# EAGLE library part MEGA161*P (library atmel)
MICROCONTROLLER 16 Kbytes FLASH 512 bytes EEPROM 1 Kbytes SRAM dual UART hardware multiplier Source: avr.lbr

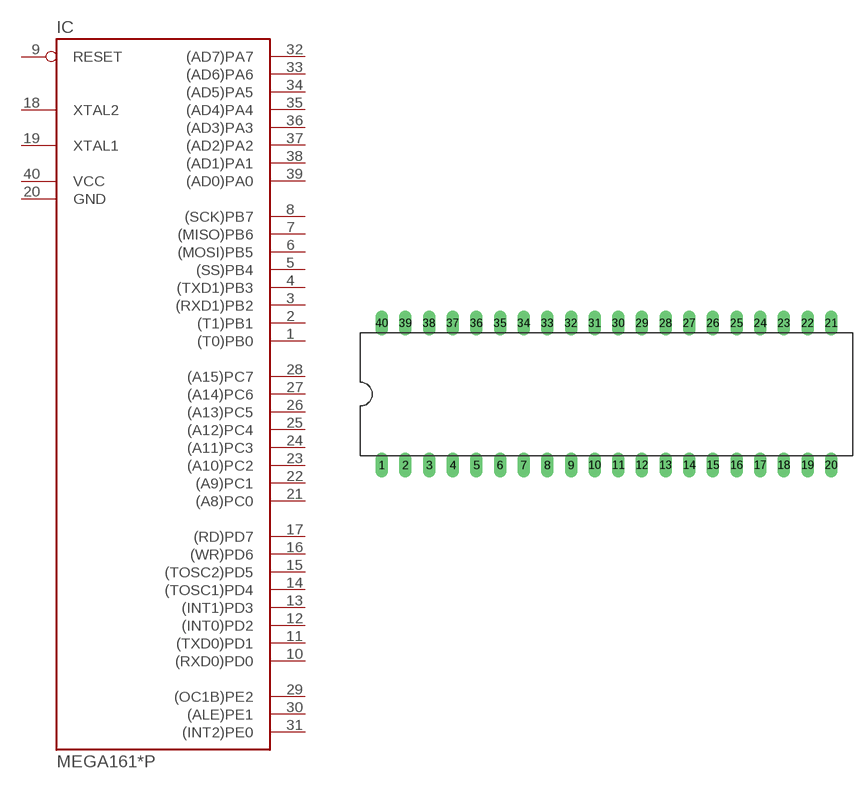
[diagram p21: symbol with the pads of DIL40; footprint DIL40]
Designator prefix IC

## MEGA161P (MPN: ATMEGA16-16PU; OC_FARNELL: 9171142; OC_NEWARK: 98M0167), MEGA161LP (MPN: ATMEGA16-16PU; OC_FARNELL: 9171142; OC_NEWARK: 98M0167)  [DIL40]
1  (T0)PB0
2  (T1)PB1
3  (RXD1)PB2
4  (TXD1)PB3
5  (SS)PB4
6  (MOSI)PB5
7  (MISO)PB6
8  (SCK)PB7
9  RESET  in
10  (RXD0)PD0
11  (TXD0)PD1
12  (INT0)PD2
13  (INT1)PD3
14  (TOSC1)PD4
15  (TOSC2)PD5
16  (WR)PD6
17  (RD)PD7
18  XTAL2  in
19  XTAL1  in
20  GND  pwr
21  (A8)PC0
22  (A9)PC1
23  (A10)PC2
24  (A11)PC3
25  (A12)PC4
26  (A13)PC5
27  (A14)PC6
28  (A15)PC7
29  (OC1B)PE2
30  (ALE)PE1
31  (INT2)PE0
32  (AD7)PA7
33  (AD6)PA6
34  (AD5)PA5
35  (AD4)PA4
36  (AD3)PA3
37  (AD2)PA2
38  (AD1)PA1
39  (AD0)PA0
40  VCC  pwr

## Footprint DIL40 (pad centres in mm)
Dual In Line
drill 0.813 long: 1 -24.13,-7.62; 2 -21.59,-7.62; 3 -19.05,-7.62; 4 -16.51,-7.62; 5 -13.97,-7.62; 6 -11.43,-7.62; 7 -8.89,-7.62; 8 -6.35,-7.62; 9 -3.81,-7.62; 10 -1.27,-7.62; 11 1.27,-7.62; 12 3.81,-7.62; 13 6.35,-7.62; 14 8.89,-7.62; 15 11.43,-7.62; 16 13.97,-7.62; 17 16.51,-7.62; 18 19.05,-7.62; 19 21.59,-7.62; 20 24.13,-7.62; 21 24.13,7.62; 22 21.59,7.62; 23 19.05,7.62; 24 16.51,7.62; 25 13.97,7.62; 26 11.43,7.62; 27 8.89,7.62; 28 6.35,7.62; 29 3.81,7.62; 30 1.27,7.62; 31 -1.27,7.62; 32 -3.81,7.62; 33 -6.35,7.62; 34 -8.89,7.62; 35 -11.43,7.62; 36 -13.97,7.62; 37 -16.51,7.62; 38 -19.05,7.62; 39 -21.59,7.62; 40 -24.13,7.62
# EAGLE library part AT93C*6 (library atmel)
3-wire serial EEPROM

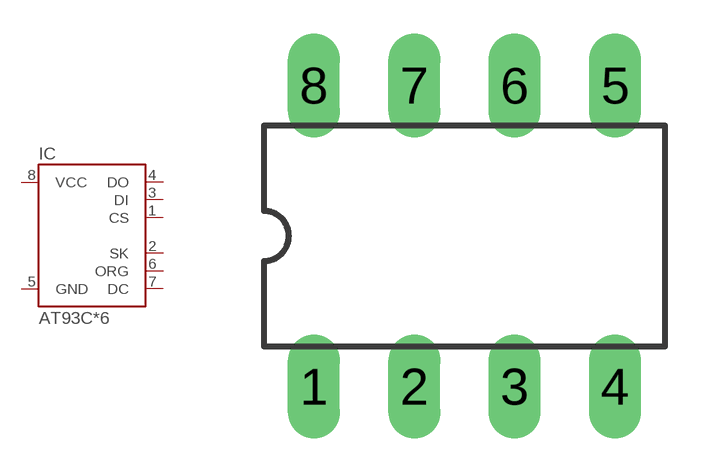
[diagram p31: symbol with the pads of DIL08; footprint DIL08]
Designator prefix IC

## AT93C6P (MPN: AT93C46D-PU; OC_FARNELL: 1362666; OC_NEWARK: 50M3339)  [DIL08]
1  CS  in
2  SK
3  DI  in
4  DO  out
5  GND  pwr
6  ORG  in
7  DC  in
8  VCC  pwr

## Footprint DIL08 (pad centres in mm)
Dual In Line
drill 0.813 long: 1 -3.81,-3.81; 2 -1.27,-3.81; 3 1.27,-3.81; 4 3.81,-3.81; 5 3.81,3.81; 6 1.27,3.81; 7 -1.27,3.81; 8 -3.81,3.81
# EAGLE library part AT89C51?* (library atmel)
8-bit Microcontroller with 4K Bytes Flash Not Recommended for New Designs. Use AT89S51. Source: http://www.atmel.com/dyn/resources/prod_documents/doc0265.

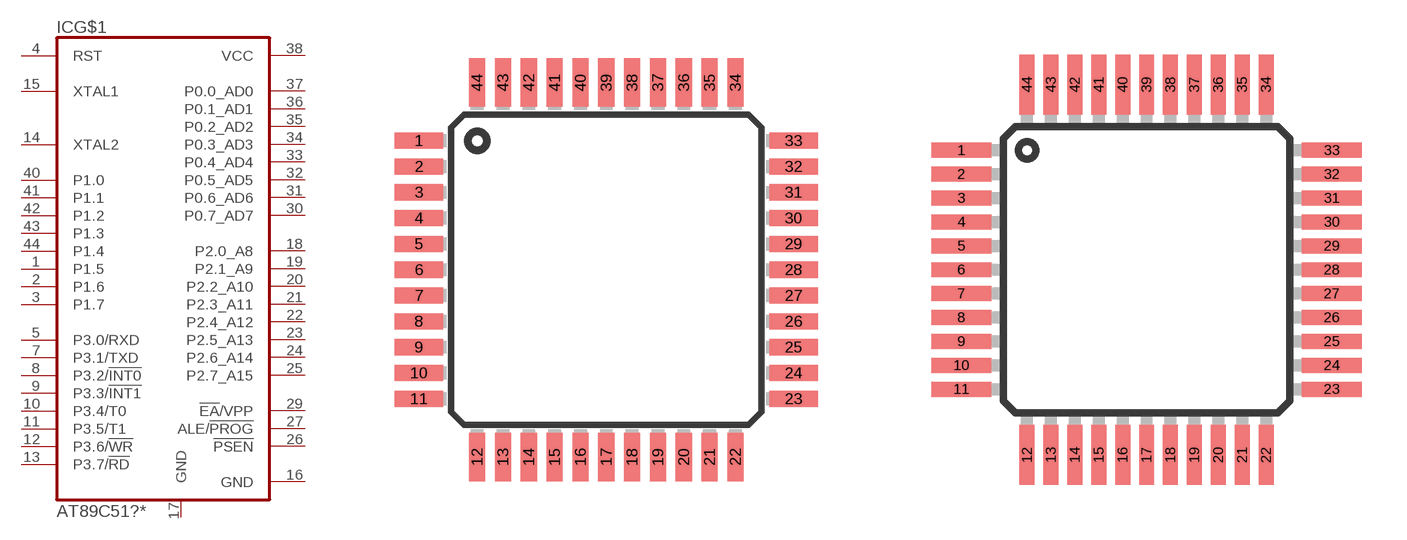
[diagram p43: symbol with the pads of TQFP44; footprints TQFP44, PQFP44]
Designator prefix IC; gates G$1=AT89C51 P=GND

## AT89C51AC-12 (OC_FARNELL: unknown; OC_NEWARK: unknown), AT89C51AC-16 (OC_FARNELL: unknown; OC_NEWARK: unknown), AT89C51AC-20 (OC_FARNELL: unknown; OC_NEWARK: unknown), AT89C51AC-24 (OC_FARNELL: unknown; OC_NEWARK: unknown)  [TQFP44]
1  G$1:P1.5
2  G$1:P1.6
3  G$1:P1.7
4  G$1:RST  in
5  G$1:P3.0/RXD
7  G$1:P3.1/TXD
8  G$1:P3.2/!INT0
9  G$1:P3.3/!INT1
10  G$1:P3.4/T0
11  G$1:P3.5/T1
12  G$1:P3.6/!WR
13  G$1:P3.7/!RD
14  G$1:XTAL2  in
15  G$1:XTAL1  in
16  G$1:GND  pwr
17  P:GND  pwr
18  G$1:P2.0_A8
19  G$1:P2.1_A9
20  G$1:P2.2_A10
21  G$1:P2.3_A11
22  G$1:P2.4_A12
23  G$1:P2.5_A13
24  G$1:P2.6_A14
25  G$1:P2.7_A15
26  G$1:!PSEN  out
27  G$1:ALE/!PROG  out
29  G$1:!EA!/VPP  in
30  G$1:P0.7_AD7
31  G$1:P0.6_AD6
32  G$1:P0.5_AD5
33  G$1:P0.4_AD4
34  G$1:P0.3_AD3
35  G$1:P0.2_AD2
36  G$1:P0.1_AD1
37  G$1:P0.0_AD0
38  G$1:VCC  pwr
40  G$1:P1.0
41  G$1:P1.1
42  G$1:P1.2
43  G$1:P1.3
44  G$1:P1.4

## AT89C51QC-12 (OC_FARNELL: unknown; OC_NEWARK: unknown), AT89C51QC-16 (OC_FARNELL: unknown; OC_NEWARK: unknown), AT89C51QC-20 (OC_FARNELL: unknown; OC_NEWARK: unknown), AT89C51QC-24 (OC_FARNELL: unknown; OC_NEWARK: unknown)  [PQFP44]
Pads as for TQFP44

## Footprint TQFP44 (pad centres in mm)
44-lead Thin Quad Flat Package
smd 1.5 x 0.5: 1 -5.8,4; 2 -5.8,3.2; 3 -5.8,2.4; 4 -5.8,1.6; 5 -5.8,0.8; 6 -5.8,0; 7 -5.8,-0.8; 8 -5.8,-1.6; 9 -5.8,-2.4; 10 -5.8,-3.2; 11 -5.8,-4; 23 5.8,-4; 24 5.8,-3.2; 25 5.8,-2.4; 26 5.8,-1.6; 27 5.8,-0.8; 28 5.8,0; 29 5.8,0.8; 30 5.8,1.6; 31 5.8,2.4; 32 5.8,3.2; 33 5.8,4
smd 0.5 x 1.5: 12 -4,-5.8; 13 -3.2,-5.8; 14 -2.4,-5.8; 15 -1.6,-5.8; 16 -0.8,-5.8; 17 0,-5.8; 18 0.8,-5.8; 19 1.6,-5.8; 20 2.4,-5.8; 21 3.2,-5.8; 22 4,-5.8; 34 4,5.8; 35 3.2,5.8; 36 2.4,5.8; 37 1.6,5.8; 38 0.8,5.8; 39 0,5.8; 40 -0.8,5.8; 41 -1.6,5.8; 42 -2.4,5.8; 43 -3.2,5.8; 44 -4,5.8

## Footprint PQFP44 (pad centres in mm)
Plastic Quad Flat Package
smd 2 x 0.5: 1 -6.2,4; 2 -6.2,3.2; 3 -6.2,2.4; 4 -6.2,1.6; 5 -6.2,0.8; 6 -6.2,0; 7 -6.2,-0.8; 8 -6.2,-1.6; 9 -6.2,-2.4; 10 -6.2,-3.2; 11 -6.2,-4; 23 6.2,-4; 24 6.2,-3.2; 25 6.2,-2.4; 26 6.2,-1.6; 27 6.2,-0.8; 28 6.2,0; 29 6.2,0.8; 30 6.2,1.6; 31 6.2,2.4; 32 6.2,3.2; 33 6.2,4
smd 0.5 x 2: 12 -4,-6.2; 13 -3.2,-6.2; 14 -2.4,-6.2; 15 -1.6,-6.2; 16 -0.8,-6.2; 17 0,-6.2; 18 0.8,-6.2; 19 1.6,-6.2; 20 2.4,-6.2; 21 3.2,-6.2; 22 4,-6.2; 34 4,6.2; 35 3.2,6.2; 36 2.4,6.2; 37 1.6,6.2; 38 0.8,6.2; 39 0,6.2; 40 -0.8,6.2; 41 -1.6,6.2; 42 -2.4,6.2; 43 -3.2,6.2; 44 -4,6.2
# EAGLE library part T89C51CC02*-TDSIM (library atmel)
Enhanced 8-bit Microcontroller with CAN Controller and Flash 80C51 Core Architecture Source: http://www.atmel.com/dyn/resources/prod_documents/doc4126.

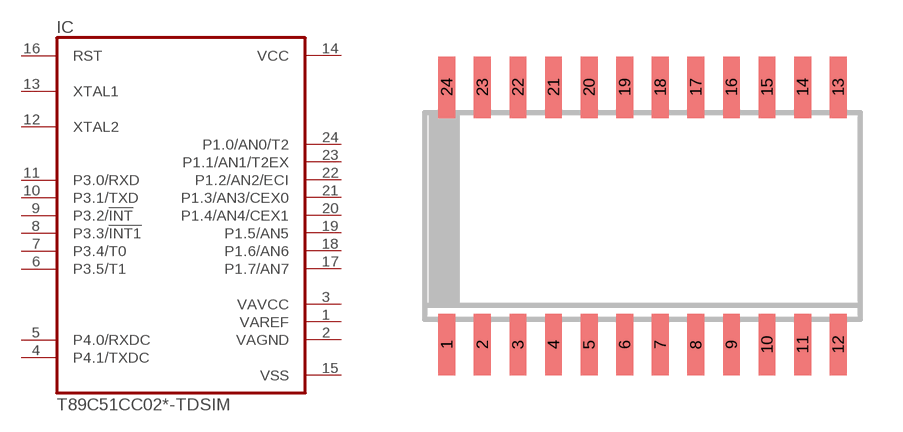
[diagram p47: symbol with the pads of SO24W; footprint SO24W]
Designator prefix IC

## T89C51CC02CA-TDSIM (OC_FARNELL: unknown; OC_NEWARK: unknown), T89C51CC02UA-TDSIM (OC_FARNELL: unknown; OC_NEWARK: unknown)  [SO24W]
1  VAREF  in
2  VAGND  in
3  VAVCC  in
4  P4.1/TXDC
5  P4.0/RXDC
6  P3.5/T1
7  P3.4/T0
8  P3.3/!INT1
9  P3.2/!INT
10  P3.1/TXD
11  P3.0/RXD
12  XTAL2  in
13  XTAL1  in
14  VCC  pwr
15  VSS  pwr
16  RST  in
17  P1.7/AN7
18  P1.6/AN6
19  P1.5/AN5
20  P1.4/AN4/CEX1
21  P1.3/AN3/CEX0
22  P1.2/AN2/ECI
23  P1.1/AN1/T2EX
24  P1.0/AN0/T2

## Footprint SO24W (pad centres in mm)
SMALL OUTLINE INTEGRATED CIRCUIT wide body 7.5 mm/JEDEC MO-119AA Source: http://www.atmel.com/dyn/resources/prod_documents/doc4126.pdf
smd 0.6 x 2.2: 1 -6.985,-4.6; 2 -5.715,-4.6; 3 -4.445,-4.6; 4 -3.175,-4.6; 5 -1.905,-4.6; 6 -0.635,-4.6; 7 0.635,-4.6; 8 1.905,-4.6; 9 3.175,-4.6; 10 4.445,-4.6; 11 5.715,-4.6; 12 6.985,-4.6; 13 6.985,4.6; 14 5.715,4.6; 15 4.445,4.6; 16 3.175,4.6; 17 1.905,4.6; 18 0.635,4.6; 19 -0.635,4.6; 20 -1.905,4.6; 21 -3.175,4.6; 22 -4.445,4.6; 23 -5.715,4.6; 24 -6.985,4.6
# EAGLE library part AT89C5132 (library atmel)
USB Microcontroller with 64K Bytes Flash Memory Source: http://www.atmel.com/dyn/resources/prod_documents/doc4173.pdf

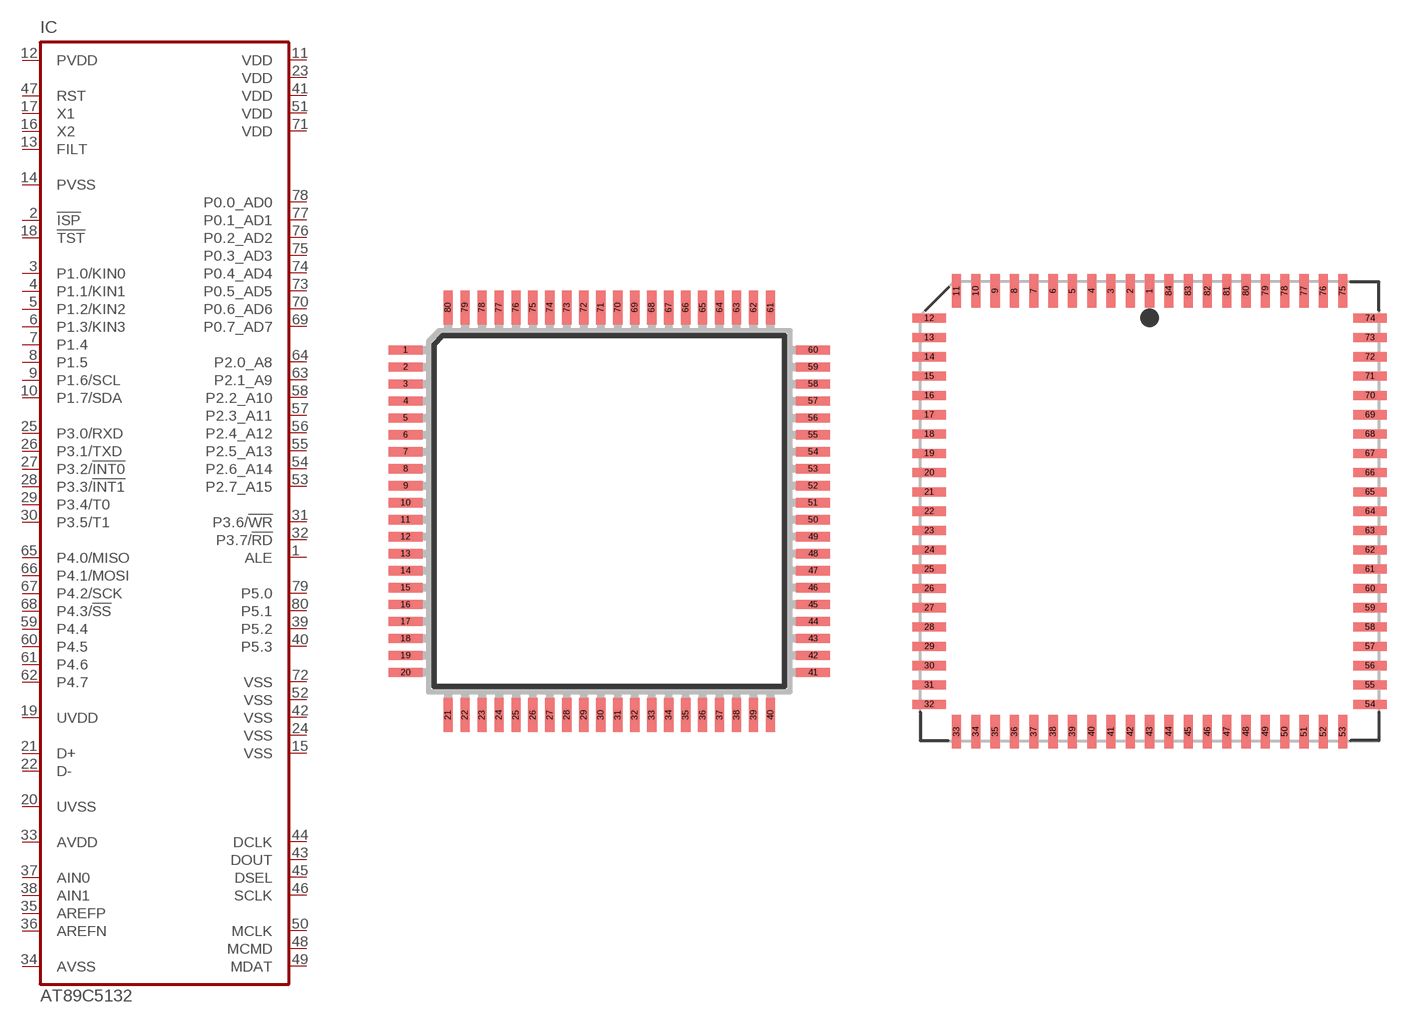
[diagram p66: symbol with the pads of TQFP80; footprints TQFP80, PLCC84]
Designator prefix IC

## AT89C5132 (OC_FARNELL: unknown; OC_NEWARK: unknown)  [TQFP80]
1  ALE
2  !ISP
3  P1.0/KIN0
4  P1.1/KIN1
5  P1.2/KIN2
6  P1.3/KIN3
7  P1.4
8  P1.5
9  P1.6/SCL
10  P1.7/SDA
11  VDD  pwr
12  PVDD  pwr
13  FILT  in
14  PVSS  pwr
15  VSS  pwr
16  X2  in
17  X1  in
18  !TST  in
19  UVDD  pwr
20  UVSS  pwr
21  D+
22  D-
23  VDD  pwr
24  VSS  pwr
25  P3.0/RXD
26  P3.1/TXD
27  P3.2/!INT0
28  P3.3/!INT1
29  P3.4/T0
30  P3.5/T1
31  P3.6/!WR
32  P3.7/!RD
33  AVDD  pwr
34  AVSS  pwr
35  AREFP  in
36  AREFN  in
37  AIN0  in
38  AIN1  in
39  P5.2
40  P5.3
41  VDD  pwr
42  VSS  pwr
43  DOUT  out
44  DCLK  out
45  DSEL  out
46  SCLK  out
47  RST  in
48  MCMD
49  MDAT
50  MCLK  out
51  VDD  pwr
52  VSS  pwr
53  P2.7_A15
54  P2.6_A14
55  P2.5_A13
56  P2.4_A12
57  P2.3_A11
58  P2.2_A10
59  P4.4
60  P4.5
61  P4.6
62  P4.7
63  P2.1_A9
64  P2.0_A8
65  P4.0/MISO
66  P4.1/MOSI
67  P4.2/SCK
68  P4.3/!SS
69  P0.7_AD7
70  P0.6_AD6
71  VDD  pwr
72  VSS  pwr
73  P0.5_AD5
74  P0.4_AD4
75  P0.3_AD3
76  P0.2_AD2
77  P0.1_AD1
78  P0.0_AD0
79  P5.0
80  P5.1

## AT89C5132DEVELOP (OC_FARNELL: unknown; OC_NEWARK: unknown)  [PLCC84]
1  VDD  pwr
2  VSS  pwr
3  P0.5_AD5
4  P0.4_AD4
5  P0.3_AD3
6  P0.2_AD2
7  P0.1_AD1
8  P0.0_AD0
9  P5.0
10  P5.1
12  ALE
13  !ISP
14  P1.0/KIN0
15  P1.1/KIN1
16  P1.2/KIN2
17  P1.3/KIN3
18  P1.4
19  P1.5
20  P1.6/SCL
21  P1.7/SDA
22  VDD  pwr
23  PVDD  pwr
24  FILT  in
25  PVSS  pwr
26  VSS  pwr
27  X2  in
29  X1  in
30  !TST  in
31  UVDD  pwr
32  UVSS  pwr
33  D+
34  D-
35  VDD  pwr
36  VSS  pwr
37  P3.0/RXD
38  P3.1/TXD
39  P3.2/!INT0
40  P3.3/!INT1
41  P3.4/T0
42  P3.5/T1
43  P3.6/!WR
44  P3.7/!RD
45  AVDD  pwr
46  AVSS  pwr
47  AREFP  in
48  AREFN  in
49  AIN0  in
50  AIN1  in
51  P5.2
52  P5.3
54  VDD  pwr
55  VSS  pwr
56  DOUT  out
57  DCLK  out
58  DSEL  out
59  SCLK  out
60  RST  in
61  MCMD
62  MDAT
63  MCLK  out
64  VDD  pwr
65  VSS  pwr
66  P2.7_A15
67  P2.6_A14
68  P2.5_A13
69  P2.4_A12
70  P2.3_A11
71  P2.2_A10
72  P4.4
73  P4.5
75  P4.6
76  P4.7
77  P2.1_A9
78  P2.0_A8
79  P4.0/MISO
80  P4.1/MOSI
81  P4.2/SCK
82  P4.3/!SS
83  P0.7_AD7
84  P0.6_AD6

## Footprint TQFP80 (pad centres in mm)
TQFP 80 thin quad flat pack Source: www.atmwel.com .. doc4109.pdf
smd 1.3 x 0.35: 1 -7.8,6.175; 2 -7.8,5.525; 3 -7.8,4.875; 4 -7.8,4.225; 5 -7.8,3.575; 6 -7.8,2.925; 7 -7.8,2.275; 8 -7.8,1.625; 9 -7.8,0.975; 10 -7.8,0.325; 11 -7.8,-0.325; 12 -7.8,-0.975; 13 -7.8,-1.625; 14 -7.8,-2.275; 15 -7.8,-2.925; 16 -7.8,-3.575; 17 -7.8,-4.225; 18 -7.8,-4.875; 19 -7.8,-5.525; 20 -7.8,-6.175; 41 7.8,-6.175; 42 7.8,-5.525; 43 7.8,-4.875; 44 7.8,-4.225; 45 7.8,-3.575; 46 7.8,-2.925; 47 7.8,-2.275; 48 7.8,-1.625; 49 7.8,-0.975; 50 7.8,-0.325; 51 7.8,0.325; 52 7.8,0.975; 53 7.8,1.625; 54 7.8,2.275; 55 7.8,2.925; 56 7.8,3.575; 57 7.8,4.225; 58 7.8,4.875; 59 7.8,5.525; 60 7.8,6.175
smd 0.35 x 1.3: 21 -6.175,-7.8; 22 -5.525,-7.8; 23 -4.875,-7.8; 24 -4.225,-7.8; 25 -3.575,-7.8; 26 -2.925,-7.8; 27 -2.275,-7.8; 28 -1.625,-7.8; 29 -0.975,-7.8; 30 -0.325,-7.8; 31 0.325,-7.8; 32 0.975,-7.8; 33 1.625,-7.8; 34 2.275,-7.8; 35 2.925,-7.8; 36 3.575,-7.8; 37 4.225,-7.8; 38 4.875,-7.8; 39 5.525,-7.8; 40 6.175,-7.8; 61 6.175,7.8; 62 5.525,7.8; 63 4.875,7.8; 64 4.225,7.8; 65 3.575,7.8; 66 2.925,7.8; 67 2.275,7.8; 68 1.625,7.8; 69 0.975,7.8; 70 0.325,7.8; 71 -0.325,7.8; 72 -0.975,7.8; 73 -1.625,7.8; 74 -2.275,7.8; 75 -2.925,7.8; 76 -3.575,7.8; 77 -4.225,7.8; 78 -4.875,7.8; 79 -5.525,7.8; 80 -6.175,7.8

## Footprint PLCC84 (pad centres in mm)
Plastic J-Lead Chip Carrier
smd 0.6 x 2.2: 1 0,14.5; 2 -1.27,14.5; 3 -2.54,14.5; 4 -3.81,14.5; 5 -5.08,14.5; 6 -6.35,14.5; 7 -7.62,14.5; 8 -8.89,14.5; 9 -10.16,14.5; 10 -11.43,14.5; 11 -12.7,14.5; 33 -12.7,-14.5; 34 -11.43,-14.5; 35 -10.16,-14.5; 36 -8.89,-14.5; 37 -7.62,-14.5; 38 -6.35,-14.5; 39 -5.08,-14.5; 40 -3.81,-14.5; 41 -2.54,-14.5; 42 -1.27,-14.5; 43 0,-14.5; 44 1.27,-14.5; 45 2.54,-14.5; 46 3.81,-14.5; 47 5.08,-14.5; 48 6.35,-14.5; 49 7.62,-14.5; 50 8.89,-14.5; 51 10.16,-14.5; 52 11.43,-14.5; 53 12.7,-14.5; 75 12.7,14.5; 76 11.43,14.5; 77 10.16,14.5; 78 8.89,14.5; 79 7.62,14.5; 80 6.35,14.5; 81 5.08,14.5; 82 3.81,14.5; 83 2.54,14.5; 84 1.27,14.5
smd 2.2 x 0.6: 12 -14.5,12.7; 13 -14.5,11.43; 14 -14.5,10.16; 15 -14.5,8.89; 16 -14.5,7.62; 17 -14.5,6.35; 18 -14.5,5.08; 19 -14.5,3.81; 20 -14.5,2.54; 21 -14.5,1.27; 22 -14.5,0; 23 -14.5,-1.27; 24 -14.5,-2.54; 25 -14.5,-3.81; 26 -14.5,-5.08; 27 -14.5,-6.35; 28 -14.5,-7.62; 29 -14.5,-8.89; 30 -14.5,-10.16; 31 -14.5,-11.43; 32 -14.5,-12.7; 54 14.5,-12.7; 55 14.5,-11.43; 56 14.5,-10.16; 57 14.5,-8.89; 58 14.5,-7.62; 59 14.5,-6.35; 60 14.5,-5.08; 61 14.5,-3.81; 62 14.5,-2.54; 63 14.5,-1.27; 64 14.5,0; 65 14.5,1.27; 66 14.5,2.54; 67 14.5,3.81; 68 14.5,5.08; 69 14.5,6.35; 70 14.5,7.62; 71 14.5,8.89; 72 14.5,10.16; 73 14.5,11.43; 74 14.5,12.7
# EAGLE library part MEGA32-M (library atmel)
MICROCONTROLLER 32 Kbytes FLASH 2 Kbytes SRAM 1 Kbytes EEPROM USART 8-channel 10 bit ADC Source: www.atmel.com .. doc2503.pdf

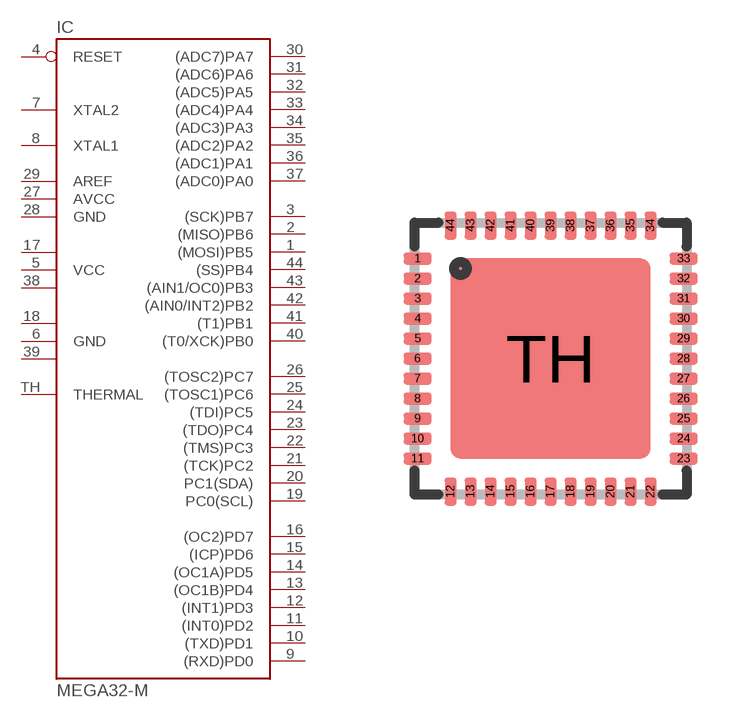
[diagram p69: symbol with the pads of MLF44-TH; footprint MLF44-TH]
Designator prefix IC

## MEGA32-M (MPN: ATMEGA32-16MU; OC_FARNELL: 1455108; OC_NEWARK: 58M3733)  [MLF44-TH]
1  (MOSI)PB5
2  (MISO)PB6
3  (SCK)PB7
4  RESET  in
5  VCC  pwr
6  GND  pwr
7  XTAL2
8  XTAL1
9  (RXD)PD0
10  (TXD)PD1
11  (INT0)PD2
12  (INT1)PD3
13  (OC1B)PD4
14  (OC1A)PD5
15  (ICP)PD6
16  (OC2)PD7
17  VCC1  pwr
18  GND1  pwr
19  PC0(SCL)
20  PC1(SDA)
21  (TCK)PC2
22  (TMS)PC3
23  (TDO)PC4
24  (TDI)PC5
25  (TOSC1)PC6
26  (TOSC2)PC7
27  AVCC  pwr
28  GND  pwr
29  AREF  pas
30  (ADC7)PA7
31  (ADC6)PA6
32  (ADC5)PA5
33  (ADC4)PA4
34  (ADC3)PA3
35  (ADC2)PA2
36  (ADC1)PA1
37  (ADC0)PA0
38  VCC2  pwr
39  GND2  pwr
40  (T0/XCK)PB0
41  (T1)PB1
42  (AIN0/INT2)PB2
43  (AIN1/OC0)PB3
44  (SS)PB4
TH  THERMAL  in

## Footprint MLF44-TH (pad centres in mm)
44M1 Micro Lead Frame package (MLF) Source: http://www.atmel.com/dyn/resources/prod_documents/doc2593.pdf
smd 0.7 x 0.3: 1 -3.325,2.5; 2 -3.325,2; 3 -3.325,1.5; 4 -3.325,1; 5 -3.325,0.5; 6 -3.325,0; 7 -3.325,-0.5; 8 -3.325,-1; 9 -3.325,-1.5; 10 -3.325,-2; 11 -3.325,-2.5; 23 3.325,-2.5; 24 3.325,-2; 25 3.325,-1.5; 26 3.325,-1; 27 3.325,-0.5; 28 3.325,0; 29 3.325,0.5; 30 3.325,1; 31 3.325,1.5; 32 3.325,2; 33 3.325,2.5
smd 0.3 x 0.7: 12 -2.5,-3.325; 13 -2,-3.325; 14 -1.5,-3.325; 15 -1,-3.325; 16 -0.5,-3.325; 17 0,-3.325; 18 0.5,-3.325; 19 1,-3.325; 20 1.5,-3.325; 21 2,-3.325; 22 2.5,-3.325; 34 2.5,3.325; 35 2,3.325; 36 1.5,3.325; 37 1,3.325; 38 0.5,3.325; 39 0,3.325; 40 -0.5,3.325; 41 -1,3.325; 42 -1.5,3.325; 43 -2,3.325; 44 -2.5,3.325
smd 5 x 5: TH 0,0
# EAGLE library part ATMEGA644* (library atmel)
8-bit Microcontroller with 64K Bytes In-System Programmable Flash Source: http://www.atmel.com/dyn/resources/prod_documents/doc2593.pdf

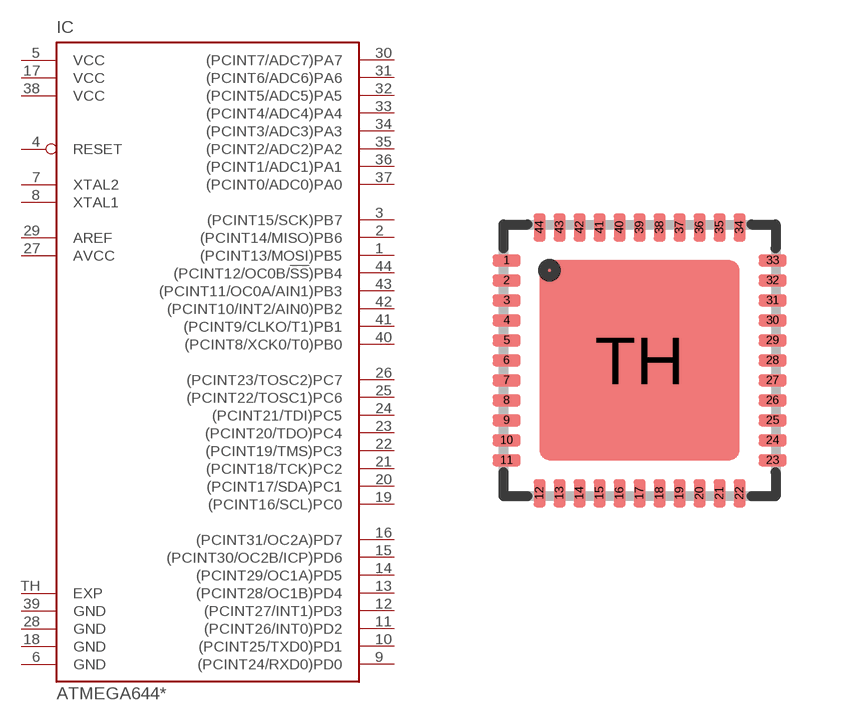
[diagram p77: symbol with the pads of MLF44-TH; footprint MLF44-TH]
Designator prefix IC

## ATMEGA644M (MPN: ATMEGA644P-20MU; OC_FARNELL: 1748528; OC_NEWARK: 26R5636)  [MLF44-TH]
1  (PCINT13/MOSI)PB5
2  (PCINT14/MISO)PB6
3  (PCINT15/SCK)PB7
4  RESET  in
5  VCC  pwr
6  GND  pwr
7  XTAL2
8  XTAL1
9  (PCINT24/RXD0)PD0
10  (PCINT25/TXD0)PD1
11  (PCINT26/INT0)PD2
12  (PCINT27/INT1)PD3
13  (PCINT28/OC1B)PD4
14  (PCINT29/OC1A)PD5
15  (PCINT30/OC2B/ICP)PD6
16  (PCINT31/OC2A)PD7
17  VCC  pwr
18  GND  pwr
19  (PCINT16/SCL)PC0  out
20  (PCINT17/SDA)PC1  out
21  (PCINT18/TCK)PC2  out
22  (PCINT19/TMS)PC3  out
23  (PCINT20/TDO)PC4  out
24  (PCINT21/TDI)PC5  out
25  (PCINT22/TOSC1)PC6  out
26  (PCINT23/TOSC2)PC7  out
27  AVCC  pwr
28  GND  pwr
29  AREF  pas
30  (PCINT7/ADC7)PA7
31  (PCINT6/ADC6)PA6
32  (PCINT5/ADC5)PA5
33  (PCINT4/ADC4)PA4
34  (PCINT3/ADC3)PA3
35  (PCINT2/ADC2)PA2
36  (PCINT1/ADC1)PA1
37  (PCINT0/ADC0)PA0
38  VCC  pwr
39  GND  pwr
40  (PCINT8/XCK0/T0)PB0
41  (PCINT9/CLKO/T1)PB1
42  (PCINT10/INT2/AIN0)PB2
43  (PCINT11/OC0A/AIN1)PB3
44  (PCINT12/OC0B/!SS!)PB4
TH  EXP  pwr

## Footprint MLF44-TH (pad centres in mm)
44M1 Micro Lead Frame package (MLF) Source: http://www.atmel.com/dyn/resources/prod_documents/doc2593.pdf
smd 0.7 x 0.3: 1 -3.325,2.5; 2 -3.325,2; 3 -3.325,1.5; 4 -3.325,1; 5 -3.325,0.5; 6 -3.325,0; 7 -3.325,-0.5; 8 -3.325,-1; 9 -3.325,-1.5; 10 -3.325,-2; 11 -3.325,-2.5; 23 3.325,-2.5; 24 3.325,-2; 25 3.325,-1.5; 26 3.325,-1; 27 3.325,-0.5; 28 3.325,0; 29 3.325,0.5; 30 3.325,1; 31 3.325,1.5; 32 3.325,2; 33 3.325,2.5
smd 0.3 x 0.7: 12 -2.5,-3.325; 13 -2,-3.325; 14 -1.5,-3.325; 15 -1,-3.325; 16 -0.5,-3.325; 17 0,-3.325; 18 0.5,-3.325; 19 1,-3.325; 20 1.5,-3.325; 21 2,-3.325; 22 2.5,-3.325; 34 2.5,3.325; 35 2,3.325; 36 1.5,3.325; 37 1,3.325; 38 0.5,3.325; 39 0,3.325; 40 -0.5,3.325; 41 -1,3.325; 42 -1.5,3.325; 43 -2,3.325; 44 -2.5,3.325
smd 5 x 5: TH 0,0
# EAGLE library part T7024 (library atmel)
Bluetooth/ISM 2.4-GHz Front-End IC Source: http://www.atmel.com/dyn/resources/prod_documents/doc4533.pdf

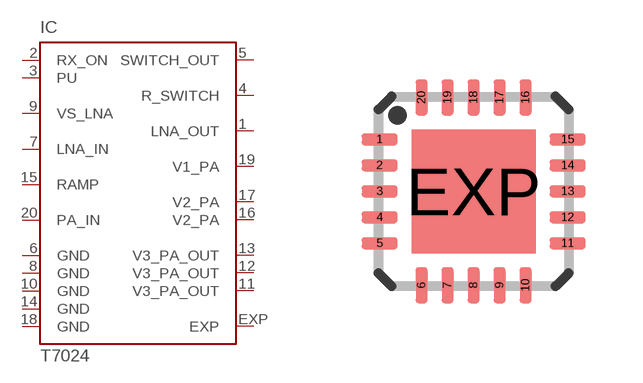
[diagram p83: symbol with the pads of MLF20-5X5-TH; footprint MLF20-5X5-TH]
Designator prefix IC

## T7024 (OC_FARNELL: unknown; OC_NEWARK: unknown)  [MLF20-5X5-TH]
1  LNA_OUT  in
2  RX_ON  in
3  PU  in
4  R_SWITCH  in
5  SWITCH_OUT  out
6  GND  pwr
7  LNA_IN  in
8  GND  pwr
9  VS_LNA  in
10  GND  pwr
11  V3_PA_OUT  pas
12  V3_PA_OUT  pas
13  V3_PA_OUT  pas
14  GND  pwr
15  RAMP  in
16  V2_PA  pas
17  V2_PA  pas
18  GND  pwr
19  V1_PA  pas
20  PA_IN  in
EXP  EXP  pas

## Footprint MLF20-5X5-TH (pad centres in mm)
HP-VFQFP-N20 QFN 20 -5 x 5 mm Micro Lead Frame package (MLF) Source: http://www.atmel.com/dyn/resources/prod_documents/doc4533.pdf
smd 0.9 x 0.3: 1 -2.35,1.3; 2 -2.35,0.65; 3 -2.35,0; 4 -2.35,-0.65; 5 -2.35,-1.3; 11 2.35,-1.3; 12 2.35,-0.65; 13 2.35,0; 14 2.35,0.65; 15 2.35,1.3
smd 0.3 x 0.9: 6 -1.3,-2.35; 7 -0.65,-2.35; 8 0,-2.35; 9 0.65,-2.35; 10 1.3,-2.35; 16 1.3,2.35; 17 0.65,2.35; 18 0,2.35; 19 -0.65,2.35; 20 -1.3,2.35
smd 3.1 x 3.1: EXP 0,0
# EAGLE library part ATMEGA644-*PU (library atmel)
8-bit Microcontroller with 64K Bytes In-System Programmable Flash Auto generated by make-symbol-device-package-bsdl.ulp Rev. 34 Source: http://www.atmel.com/dyn/resources/prod_documents/doc2593.pdf

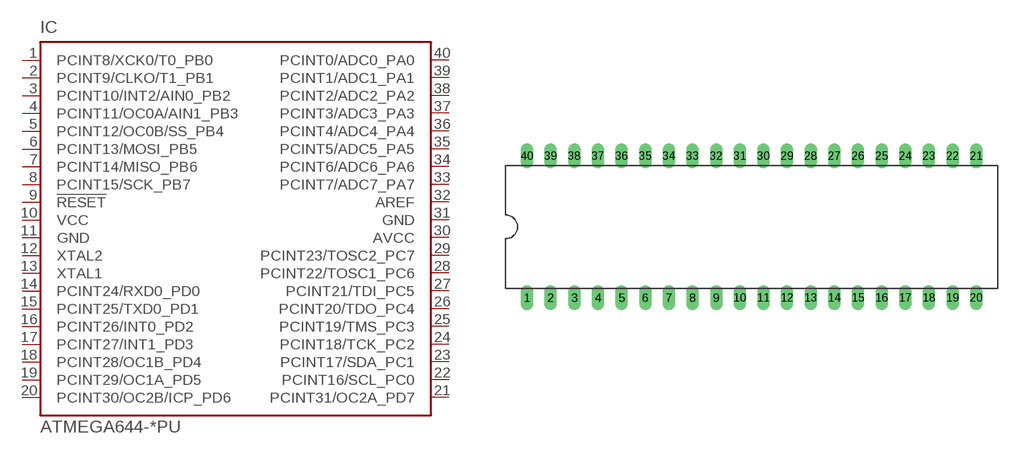
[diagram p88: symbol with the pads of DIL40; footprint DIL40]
Designator prefix IC

## ATMEGA644-10PU (MPN: ATMEGA644V-10PU; OC_FARNELL: 1288342; OC_NEWARK: 23M5062), ATMEGA644-20PU (MPN: ATMEGA644-20PU; OC_FARNELL: 1288340; OC_NEWARK: 23M5060)  [DIL40]
1  PCINT8/XCK0/T0_PB0
2  PCINT9/CLKO/T1_PB1
3  PCINT10/INT2/AIN0_PB2
4  PCINT11/OC0A/AIN1_PB3
5  PCINT12/OC0B/SS_PB4
6  PCINT13/MOSI_PB5
7  PCINT14/MISO_PB6
8  PCINT15/SCK_PB7
9  !RESET  in
10  VCC  pwr
11  GND  pwr
12  XTAL2  out
13  XTAL1  in
14  PCINT24/RXD0_PD0
15  PCINT25/TXD0_PD1
16  PCINT26/INT0_PD2
17  PCINT27/INT1_PD3
18  PCINT28/OC1B_PD4
19  PCINT29/OC1A_PD5
20  PCINT30/OC2B/ICP_PD6
21  PCINT31/OC2A_PD7
22  PCINT16/SCL_PC0
23  PCINT17/SDA_PC1
24  PCINT18/TCK_PC2
25  PCINT19/TMS_PC3
26  PCINT20/TDO_PC4
27  PCINT21/TDI_PC5
28  PCINT22/TOSC1_PC6
29  PCINT23/TOSC2_PC7
30  AVCC  pwr
31  GND  pwr
32  AREF  pas
33  PCINT7/ADC7_PA7
34  PCINT6/ADC6_PA6
35  PCINT5/ADC5_PA5
36  PCINT4/ADC4_PA4
37  PCINT3/ADC3_PA3
38  PCINT2/ADC2_PA2
39  PCINT1/ADC1_PA1
40  PCINT0/ADC0_PA0

## Footprint DIL40 (pad centres in mm)
Dual In Line
drill 0.813 long: 1 -24.13,-7.62; 2 -21.59,-7.62; 3 -19.05,-7.62; 4 -16.51,-7.62; 5 -13.97,-7.62; 6 -11.43,-7.62; 7 -8.89,-7.62; 8 -6.35,-7.62; 9 -3.81,-7.62; 10 -1.27,-7.62; 11 1.27,-7.62; 12 3.81,-7.62; 13 6.35,-7.62; 14 8.89,-7.62; 15 11.43,-7.62; 16 13.97,-7.62; 17 16.51,-7.62; 18 19.05,-7.62; 19 21.59,-7.62; 20 24.13,-7.62; 21 24.13,7.62; 22 21.59,7.62; 23 19.05,7.62; 24 16.51,7.62; 25 13.97,7.62; 26 11.43,7.62; 27 8.89,7.62; 28 6.35,7.62; 29 3.81,7.62; 30 1.27,7.62; 31 -1.27,7.62; 32 -3.81,7.62; 33 -6.35,7.62; 34 -8.89,7.62; 35 -11.43,7.62; 36 -13.97,7.62; 37 -16.51,7.62; 38 -19.05,7.62; 39 -21.59,7.62; 40 -24.13,7.62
